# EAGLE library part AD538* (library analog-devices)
Real-Time Analog Computational Unit (ACU)

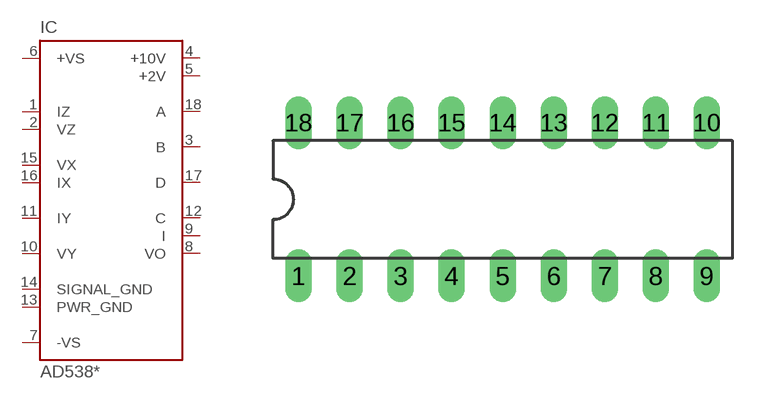
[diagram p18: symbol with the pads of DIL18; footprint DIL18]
Designator prefix IC

## AD538AD, AD538BD, AD538SD  [DIL18]
1  IZ  pas
2  VZ  in
3  B  out
4  +10V  out
5  +2V  out
6  +VS  pwr
7  -VS  pwr
8  VO  out
9  I  pas
10  VY  in
11  IY  pas
12  C  pas
13  PWR_GND  pwr
14  SIGNAL_GND  pwr
15  VX  in
16  IX  pas
17  D  pas
18  A  pas

## Footprint DIL18 (pad centres in mm)
Dual In Line Package
drill 0.813 long: 1 -10.16,-3.81; 2 -7.62,-3.81; 3 -5.08,-3.81; 4 -2.54,-3.81; 5 0,-3.81; 6 2.54,-3.81; 7 5.08,-3.81; 8 7.62,-3.81; 9 10.16,-3.81; 10 10.16,3.81; 11 7.62,3.81; 12 5.08,3.81; 13 2.54,3.81; 14 0,3.81; 15 -2.54,3.81; 16 -5.08,3.81; 17 -7.62,3.81; 18 -10.16,3.81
